VERSION 5.7 ;
  NOWIREEXTENSIONATPIN ON ;
  DIVIDERCHAR "/" ;
  BUSBITCHARS "[]" ;
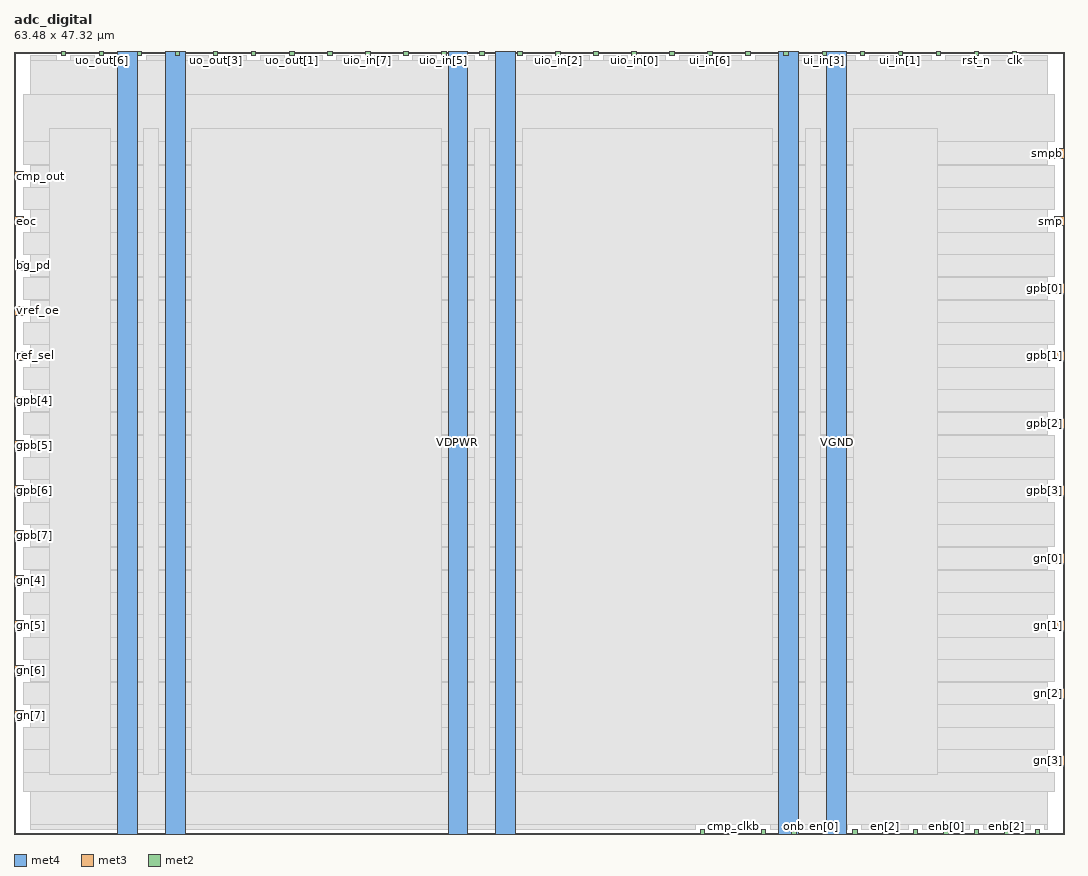
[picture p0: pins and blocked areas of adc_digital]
MACRO adc_digital
  CLASS BLOCK ;
  FOREIGN adc_digital ;
  ORIGIN 0.000 0.000 ;
  SIZE 63.480 BY 47.320 ;
  PIN VDPWR
    DIRECTION INOUT ;
    USE POWER ;
    PORT
      LAYER met4 ;
        RECT 6.240 0.000 7.440 47.320 ;
    END
    PORT
      LAYER met4 ;
        RECT 26.240 0.000 27.440 47.320 ;
    END
    PORT
      LAYER met4 ;
        RECT 46.240 0.000 47.440 47.320 ;
    END
  END VDPWR
  PIN VGND
    DIRECTION INOUT ;
    USE GROUND ;
    PORT
      LAYER met4 ;
        RECT 9.140 0.000 10.340 47.320 ;
    END
    PORT
      LAYER met4 ;
        RECT 29.140 0.000 30.340 47.320 ;
    END
    PORT
      LAYER met4 ;
        RECT 49.140 0.000 50.340 47.320 ;
    END
  END VGND
  PIN bg_pd
    DIRECTION OUTPUT ;
    USE SIGNAL ;
    ANTENNADIFFAREA 0.445500 ;
    PORT
      LAYER met3 ;
        RECT 0.000 34.040 0.600 34.640 ;
    END
  END bg_pd
  PIN clk
    DIRECTION INPUT ;
    USE SIGNAL ;
    ANTENNAGATEAREA 0.852000 ;
    PORT
      LAYER met2 ;
        RECT 60.350 47.040 60.630 47.320 ;
    END
  END clk
  PIN cmp_clkb
    DIRECTION OUTPUT ;
    USE SIGNAL ;
    ANTENNADIFFAREA 1.141000 ;
    PORT
      LAYER met2 ;
        RECT 43.330 0.000 43.610 0.280 ;
    END
  END cmp_clkb
  PIN cmp_out
    DIRECTION OUTPUT ;
    USE SIGNAL ;
    ANTENNADIFFAREA 0.795200 ;
    PORT
      LAYER met3 ;
        RECT 0.000 39.480 0.600 40.080 ;
    END
  END cmp_out
  PIN en[0]
    DIRECTION OUTPUT ;
    USE SIGNAL ;
    ANTENNADIFFAREA 0.445500 ;
    PORT
      LAYER met2 ;
        RECT 48.850 0.000 49.130 0.280 ;
    END
  END en[0]
  PIN en[1]
    DIRECTION OUTPUT ;
    USE SIGNAL ;
    ANTENNADIFFAREA 0.445500 ;
    PORT
      LAYER met2 ;
        RECT 50.690 0.000 50.970 0.280 ;
    END
  END en[1]
  PIN en[2]
    DIRECTION OUTPUT ;
    USE SIGNAL ;
    ANTENNADIFFAREA 0.445500 ;
    PORT
      LAYER met2 ;
        RECT 52.530 0.000 52.810 0.280 ;
    END
  END en[2]
  PIN en[3]
    DIRECTION OUTPUT ;
    USE SIGNAL ;
    ANTENNADIFFAREA 0.445500 ;
    PORT
      LAYER met2 ;
        RECT 54.370 0.000 54.650 0.280 ;
    END
  END en[3]
  PIN enb[0]
    DIRECTION OUTPUT ;
    USE SIGNAL ;
    ANTENNAGATEAREA 0.495000 ;
    ANTENNADIFFAREA 0.445500 ;
    PORT
      LAYER met2 ;
        RECT 56.210 0.000 56.490 0.280 ;
    END
  END enb[0]
  PIN enb[1]
    DIRECTION OUTPUT ;
    USE SIGNAL ;
    ANTENNAGATEAREA 0.495000 ;
    ANTENNADIFFAREA 0.775500 ;
    PORT
      LAYER met2 ;
        RECT 58.050 0.000 58.330 0.280 ;
    END
  END enb[1]
  PIN enb[2]
    DIRECTION OUTPUT ;
    USE SIGNAL ;
    ANTENNAGATEAREA 0.495000 ;
    ANTENNADIFFAREA 0.775500 ;
    PORT
      LAYER met2 ;
        RECT 59.890 0.000 60.170 0.280 ;
    END
  END enb[2]
  PIN enb[3]
    DIRECTION OUTPUT ;
    USE SIGNAL ;
    ANTENNAGATEAREA 0.495000 ;
    ANTENNADIFFAREA 0.715500 ;
    PORT
      LAYER met2 ;
        RECT 61.730 0.000 62.010 0.280 ;
    END
  END enb[3]
  PIN eoc
    DIRECTION OUTPUT ;
    USE SIGNAL ;
    ANTENNADIFFAREA 0.445500 ;
    PORT
      LAYER met3 ;
        RECT 0.000 36.760 0.600 37.360 ;
    END
  END eoc
  PIN gn[0]
    DIRECTION OUTPUT ;
    USE SIGNAL ;
    ANTENNADIFFAREA 0.795200 ;
    PORT
      LAYER met3 ;
        RECT 62.880 16.360 63.480 16.960 ;
    END
  END gn[0]
  PIN gn[1]
    DIRECTION OUTPUT ;
    USE SIGNAL ;
    ANTENNADIFFAREA 0.795200 ;
    PORT
      LAYER met3 ;
        RECT 62.880 12.280 63.480 12.880 ;
    END
  END gn[1]
  PIN gn[2]
    DIRECTION OUTPUT ;
    USE SIGNAL ;
    ANTENNADIFFAREA 0.795200 ;
    PORT
      LAYER met3 ;
        RECT 62.880 8.200 63.480 8.800 ;
    END
  END gn[2]
  PIN gn[3]
    DIRECTION OUTPUT ;
    USE SIGNAL ;
    ANTENNADIFFAREA 0.795200 ;
    PORT
      LAYER met3 ;
        RECT 62.880 4.120 63.480 4.720 ;
    END
  END gn[3]
  PIN gn[4]
    DIRECTION OUTPUT ;
    USE SIGNAL ;
    ANTENNADIFFAREA 0.795200 ;
    PORT
      LAYER met3 ;
        RECT 0.000 15.000 0.600 15.600 ;
    END
  END gn[4]
  PIN gn[5]
    DIRECTION OUTPUT ;
    USE SIGNAL ;
    ANTENNADIFFAREA 0.795200 ;
    PORT
      LAYER met3 ;
        RECT 0.000 12.280 0.600 12.880 ;
    END
  END gn[5]
  PIN gn[6]
    DIRECTION OUTPUT ;
    USE SIGNAL ;
    ANTENNADIFFAREA 0.795200 ;
    PORT
      LAYER met3 ;
        RECT 0.000 9.560 0.600 10.160 ;
    END
  END gn[6]
  PIN gn[7]
    DIRECTION OUTPUT ;
    USE SIGNAL ;
    ANTENNADIFFAREA 0.795200 ;
    PORT
      LAYER met3 ;
        RECT 0.000 6.840 0.600 7.440 ;
    END
  END gn[7]
  PIN gpb[0]
    DIRECTION OUTPUT ;
    USE SIGNAL ;
    ANTENNADIFFAREA 0.715500 ;
    PORT
      LAYER met3 ;
        RECT 62.880 32.680 63.480 33.280 ;
    END
  END gpb[0]
  PIN gpb[1]
    DIRECTION OUTPUT ;
    USE SIGNAL ;
    ANTENNADIFFAREA 0.715500 ;
    PORT
      LAYER met3 ;
        RECT 62.880 28.600 63.480 29.200 ;
    END
  END gpb[1]
  PIN gpb[2]
    DIRECTION OUTPUT ;
    USE SIGNAL ;
    ANTENNADIFFAREA 0.715500 ;
    PORT
      LAYER met3 ;
        RECT 62.880 24.520 63.480 25.120 ;
    END
  END gpb[2]
  PIN gpb[3]
    DIRECTION OUTPUT ;
    USE SIGNAL ;
    ANTENNADIFFAREA 0.715500 ;
    PORT
      LAYER met3 ;
        RECT 62.880 20.440 63.480 21.040 ;
    END
  END gpb[3]
  PIN gpb[4]
    DIRECTION OUTPUT ;
    USE SIGNAL ;
    ANTENNADIFFAREA 0.715500 ;
    PORT
      LAYER met3 ;
        RECT 0.000 25.880 0.600 26.480 ;
    END
  END gpb[4]
  PIN gpb[5]
    DIRECTION OUTPUT ;
    USE SIGNAL ;
    ANTENNADIFFAREA 0.715500 ;
    PORT
      LAYER met3 ;
        RECT 0.000 23.160 0.600 23.760 ;
    END
  END gpb[5]
  PIN gpb[6]
    DIRECTION OUTPUT ;
    USE SIGNAL ;
    ANTENNADIFFAREA 0.715500 ;
    PORT
      LAYER met3 ;
        RECT 0.000 20.440 0.600 21.040 ;
    END
  END gpb[6]
  PIN gpb[7]
    DIRECTION OUTPUT ;
    USE SIGNAL ;
    ANTENNADIFFAREA 0.715500 ;
    PORT
      LAYER met3 ;
        RECT 0.000 17.720 0.600 18.320 ;
    END
  END gpb[7]
  PIN onb
    DIRECTION INPUT ;
    USE SIGNAL ;
    ANTENNAGATEAREA 0.247500 ;
    PORT
      LAYER met2 ;
        RECT 47.010 0.000 47.290 0.280 ;
    END
  END onb
  PIN opb
    DIRECTION INPUT ;
    USE SIGNAL ;
    ANTENNAGATEAREA 0.247500 ;
    PORT
      LAYER met2 ;
        RECT 45.170 0.000 45.450 0.280 ;
    END
  END opb
  PIN ref_sel
    DIRECTION OUTPUT ;
    USE SIGNAL ;
    ANTENNADIFFAREA 0.445500 ;
    PORT
      LAYER met3 ;
        RECT 0.000 28.600 0.600 29.200 ;
    END
  END ref_sel
  PIN rst_n
    DIRECTION INPUT ;
    USE SIGNAL ;
    ANTENNAGATEAREA 0.213000 ;
    PORT
      LAYER met2 ;
        RECT 58.050 47.040 58.330 47.320 ;
    END
  END rst_n
  PIN smp
    DIRECTION OUTPUT ;
    USE SIGNAL ;
    ANTENNAGATEAREA 2.475000 ;
    ANTENNADIFFAREA 1.336500 ;
    PORT
      LAYER met3 ;
        RECT 62.880 36.760 63.480 37.360 ;
    END
  END smp
  PIN smpb
    DIRECTION OUTPUT ;
    USE SIGNAL ;
    ANTENNAGATEAREA 3.960000 ;
    ANTENNADIFFAREA 0.445500 ;
    PORT
      LAYER met3 ;
        RECT 62.880 40.840 63.480 41.440 ;
    END
  END smpb
  PIN smpt
    DIRECTION OUTPUT ;
    USE SIGNAL ;
    ANTENNADIFFAREA 0.453750 ;
    PORT
      LAYER met2 ;
        RECT 41.490 0.000 41.770 0.280 ;
    END
  END smpt
  PIN ui_in[0]
    DIRECTION INPUT ;
    USE SIGNAL ;
    ANTENNAGATEAREA 0.499500 ;
    PORT
      LAYER met2 ;
        RECT 55.750 47.040 56.030 47.320 ;
    END
  END ui_in[0]
  PIN ui_in[1]
    DIRECTION INPUT ;
    USE SIGNAL ;
    ANTENNAGATEAREA 0.499500 ;
    PORT
      LAYER met2 ;
        RECT 53.450 47.040 53.730 47.320 ;
    END
  END ui_in[1]
  PIN ui_in[2]
    DIRECTION INPUT ;
    USE SIGNAL ;
    ANTENNAGATEAREA 0.373500 ;
    PORT
      LAYER met2 ;
        RECT 51.150 47.040 51.430 47.320 ;
    END
  END ui_in[2]
  PIN ui_in[3]
    DIRECTION INPUT ;
    USE SIGNAL ;
    ANTENNAGATEAREA 0.499500 ;
    PORT
      LAYER met2 ;
        RECT 48.850 47.040 49.130 47.320 ;
    END
  END ui_in[3]
  PIN ui_in[4]
    DIRECTION INPUT ;
    USE SIGNAL ;
    ANTENNAGATEAREA 0.373500 ;
    PORT
      LAYER met2 ;
        RECT 46.550 47.040 46.830 47.320 ;
    END
  END ui_in[4]
  PIN ui_in[5]
    DIRECTION INPUT ;
    USE SIGNAL ;
    ANTENNAGATEAREA 0.373500 ;
    PORT
      LAYER met2 ;
        RECT 44.250 47.040 44.530 47.320 ;
    END
  END ui_in[5]
  PIN ui_in[6]
    DIRECTION INPUT ;
    USE SIGNAL ;
    ANTENNAGATEAREA 0.373500 ;
    PORT
      LAYER met2 ;
        RECT 41.950 47.040 42.230 47.320 ;
    END
  END ui_in[6]
  PIN ui_in[7]
    DIRECTION INPUT ;
    USE SIGNAL ;
    ANTENNAGATEAREA 0.373500 ;
    PORT
      LAYER met2 ;
        RECT 39.650 47.040 39.930 47.320 ;
    END
  END ui_in[7]
  PIN uio_in[0]
    DIRECTION INPUT ;
    USE SIGNAL ;
    ANTENNAGATEAREA 0.639000 ;
    PORT
      LAYER met2 ;
        RECT 37.350 47.040 37.630 47.320 ;
    END
  END uio_in[0]
  PIN uio_in[1]
    DIRECTION INPUT ;
    USE SIGNAL ;
    ANTENNAGATEAREA 0.126000 ;
    PORT
      LAYER met2 ;
        RECT 35.050 47.040 35.330 47.320 ;
    END
  END uio_in[1]
  PIN uio_in[2]
    DIRECTION INPUT ;
    USE SIGNAL ;
    ANTENNAGATEAREA 0.495000 ;
    PORT
      LAYER met2 ;
        RECT 32.750 47.040 33.030 47.320 ;
    END
  END uio_in[2]
  PIN uio_in[3]
    DIRECTION INPUT ;
    USE SIGNAL ;
    ANTENNAGATEAREA 0.159000 ;
    PORT
      LAYER met2 ;
        RECT 30.450 47.040 30.730 47.320 ;
    END
  END uio_in[3]
  PIN uio_in[4]
    DIRECTION INPUT ;
    USE SIGNAL ;
    PORT
      LAYER met2 ;
        RECT 28.150 47.040 28.430 47.320 ;
    END
  END uio_in[4]
  PIN uio_in[5]
    DIRECTION INPUT ;
    USE SIGNAL ;
    PORT
      LAYER met2 ;
        RECT 25.850 47.040 26.130 47.320 ;
    END
  END uio_in[5]
  PIN uio_in[6]
    DIRECTION INPUT ;
    USE SIGNAL ;
    ANTENNAGATEAREA 1.242000 ;
    PORT
      LAYER met2 ;
        RECT 23.550 47.040 23.830 47.320 ;
    END
  END uio_in[6]
  PIN uio_in[7]
    DIRECTION INPUT ;
    USE SIGNAL ;
    ANTENNAGATEAREA 1.242000 ;
    PORT
      LAYER met2 ;
        RECT 21.250 47.040 21.530 47.320 ;
    END
  END uio_in[7]
  PIN uo_out[0]
    DIRECTION OUTPUT ;
    USE SIGNAL ;
    ANTENNADIFFAREA 0.429000 ;
    PORT
      LAYER met2 ;
        RECT 18.950 47.040 19.230 47.320 ;
    END
  END uo_out[0]
  PIN uo_out[1]
    DIRECTION OUTPUT ;
    USE SIGNAL ;
    ANTENNADIFFAREA 0.429000 ;
    PORT
      LAYER met2 ;
        RECT 16.650 47.040 16.930 47.320 ;
    END
  END uo_out[1]
  PIN uo_out[2]
    DIRECTION OUTPUT ;
    USE SIGNAL ;
    ANTENNADIFFAREA 0.429000 ;
    PORT
      LAYER met2 ;
        RECT 14.350 47.040 14.630 47.320 ;
    END
  END uo_out[2]
  PIN uo_out[3]
    DIRECTION OUTPUT ;
    USE SIGNAL ;
    ANTENNADIFFAREA 0.429000 ;
    PORT
      LAYER met2 ;
        RECT 12.050 47.040 12.330 47.320 ;
    END
  END uo_out[3]
  PIN uo_out[4]
    DIRECTION OUTPUT ;
    USE SIGNAL ;
    ANTENNADIFFAREA 0.429000 ;
    PORT
      LAYER met2 ;
        RECT 9.750 47.040 10.030 47.320 ;
    END
  END uo_out[4]
  PIN uo_out[5]
    DIRECTION OUTPUT ;
    USE SIGNAL ;
    ANTENNADIFFAREA 0.429000 ;
    PORT
      LAYER met2 ;
        RECT 7.450 47.040 7.730 47.320 ;
    END
  END uo_out[5]
  PIN uo_out[6]
    DIRECTION OUTPUT ;
    USE SIGNAL ;
    ANTENNADIFFAREA 0.429000 ;
    PORT
      LAYER met2 ;
        RECT 5.150 47.040 5.430 47.320 ;
    END
  END uo_out[6]
  PIN uo_out[7]
    DIRECTION OUTPUT ;
    USE SIGNAL ;
    ANTENNADIFFAREA 0.429000 ;
    PORT
      LAYER met2 ;
        RECT 2.850 47.040 3.130 47.320 ;
    END
  END uo_out[7]
  PIN vref_oe
    DIRECTION OUTPUT ;
    USE SIGNAL ;
    ANTENNADIFFAREA 0.445500 ;
    PORT
      LAYER met3 ;
        RECT 0.000 31.320 0.600 31.920 ;
    END
  END vref_oe
  OBS
      LAYER nwell ;
        RECT 1.650 2.635 61.830 43.710 ;
      LAYER li1 ;
        RECT 1.840 2.635 61.640 43.605 ;
      LAYER met1 ;
        RECT 0.990 1.060 62.490 44.840 ;
      LAYER met2 ;
        RECT 1.010 46.760 2.570 47.040 ;
        RECT 3.410 46.760 4.870 47.040 ;
        RECT 5.710 46.760 7.170 47.040 ;
        RECT 8.010 46.760 9.470 47.040 ;
        RECT 10.310 46.760 11.770 47.040 ;
        RECT 12.610 46.760 14.070 47.040 ;
        RECT 14.910 46.760 16.370 47.040 ;
        RECT 17.210 46.760 18.670 47.040 ;
        RECT 19.510 46.760 20.970 47.040 ;
        RECT 21.810 46.760 23.270 47.040 ;
        RECT 24.110 46.760 25.570 47.040 ;
        RECT 26.410 46.760 27.870 47.040 ;
        RECT 28.710 46.760 30.170 47.040 ;
        RECT 31.010 46.760 32.470 47.040 ;
        RECT 33.310 46.760 34.770 47.040 ;
        RECT 35.610 46.760 37.070 47.040 ;
        RECT 37.910 46.760 39.370 47.040 ;
        RECT 40.210 46.760 41.670 47.040 ;
        RECT 42.510 46.760 43.970 47.040 ;
        RECT 44.810 46.760 46.270 47.040 ;
        RECT 47.110 46.760 48.570 47.040 ;
        RECT 49.410 46.760 50.870 47.040 ;
        RECT 51.710 46.760 53.170 47.040 ;
        RECT 54.010 46.760 55.470 47.040 ;
        RECT 56.310 46.760 57.770 47.040 ;
        RECT 58.610 46.760 60.070 47.040 ;
        RECT 60.910 46.760 62.470 47.040 ;
        RECT 1.010 0.560 62.470 46.760 ;
        RECT 1.010 0.280 41.210 0.560 ;
        RECT 42.050 0.280 43.050 0.560 ;
        RECT 43.890 0.280 44.890 0.560 ;
        RECT 45.730 0.280 46.730 0.560 ;
        RECT 47.570 0.280 48.570 0.560 ;
        RECT 49.410 0.280 50.410 0.560 ;
        RECT 51.250 0.280 52.250 0.560 ;
        RECT 53.090 0.280 54.090 0.560 ;
        RECT 54.930 0.280 55.930 0.560 ;
        RECT 56.770 0.280 57.770 0.560 ;
        RECT 58.610 0.280 59.610 0.560 ;
        RECT 60.450 0.280 61.450 0.560 ;
        RECT 62.290 0.280 62.470 0.560 ;
      LAYER met3 ;
        RECT 0.600 41.840 62.880 44.705 ;
        RECT 0.600 40.480 62.480 41.840 ;
        RECT 1.000 40.440 62.480 40.480 ;
        RECT 1.000 39.080 62.880 40.440 ;
        RECT 0.600 37.760 62.880 39.080 ;
        RECT 1.000 36.360 62.480 37.760 ;
        RECT 0.600 35.040 62.880 36.360 ;
        RECT 1.000 33.680 62.880 35.040 ;
        RECT 1.000 33.640 62.480 33.680 ;
        RECT 0.600 32.320 62.480 33.640 ;
        RECT 1.000 32.280 62.480 32.320 ;
        RECT 1.000 30.920 62.880 32.280 ;
        RECT 0.600 29.600 62.880 30.920 ;
        RECT 1.000 28.200 62.480 29.600 ;
        RECT 0.600 26.880 62.880 28.200 ;
        RECT 1.000 25.520 62.880 26.880 ;
        RECT 1.000 25.480 62.480 25.520 ;
        RECT 0.600 24.160 62.480 25.480 ;
        RECT 1.000 24.120 62.480 24.160 ;
        RECT 1.000 22.760 62.880 24.120 ;
        RECT 0.600 21.440 62.880 22.760 ;
        RECT 1.000 20.040 62.480 21.440 ;
        RECT 0.600 18.720 62.880 20.040 ;
        RECT 1.000 17.360 62.880 18.720 ;
        RECT 1.000 17.320 62.480 17.360 ;
        RECT 0.600 16.000 62.480 17.320 ;
        RECT 1.000 15.960 62.480 16.000 ;
        RECT 1.000 14.600 62.880 15.960 ;
        RECT 0.600 13.280 62.880 14.600 ;
        RECT 1.000 11.880 62.480 13.280 ;
        RECT 0.600 10.560 62.880 11.880 ;
        RECT 1.000 9.200 62.880 10.560 ;
        RECT 1.000 9.160 62.480 9.200 ;
        RECT 0.600 7.840 62.480 9.160 ;
        RECT 1.000 7.800 62.480 7.840 ;
        RECT 1.000 6.440 62.880 7.800 ;
        RECT 0.600 5.120 62.880 6.440 ;
        RECT 0.600 3.720 62.480 5.120 ;
        RECT 0.600 2.555 62.880 3.720 ;
      LAYER met4 ;
        RECT 2.135 3.575 5.840 42.665 ;
        RECT 7.840 3.575 8.740 42.665 ;
        RECT 10.740 3.575 25.840 42.665 ;
        RECT 27.840 3.575 28.740 42.665 ;
        RECT 30.740 3.575 45.840 42.665 ;
        RECT 47.840 3.575 48.740 42.665 ;
        RECT 50.740 3.575 55.825 42.665 ;
  END
END adc_digital
END LIBRARY

